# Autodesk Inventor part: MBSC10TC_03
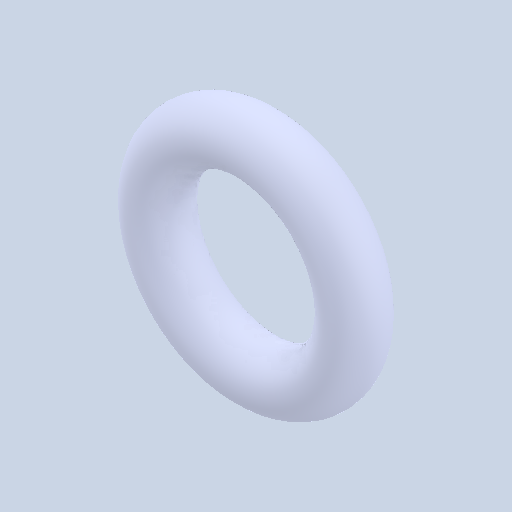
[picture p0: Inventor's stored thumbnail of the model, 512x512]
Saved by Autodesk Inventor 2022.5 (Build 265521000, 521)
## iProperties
Created: 2024-05
Part Number: MBSC10TC_03
Material: 一般
Document SubType Name: Modeling
Designer: ImaoCorp
Density: 1 g/cm^3
Appearance: 既定
Author: ImaoCorp
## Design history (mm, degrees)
feature "MBSC10TC_03"
node "ソリッド1"
